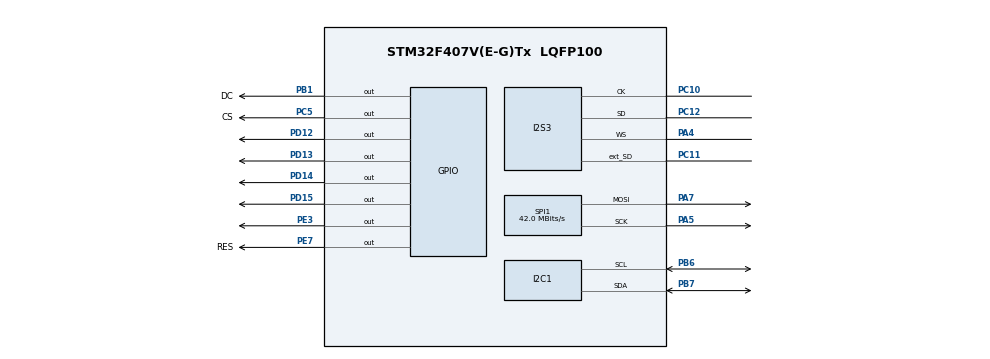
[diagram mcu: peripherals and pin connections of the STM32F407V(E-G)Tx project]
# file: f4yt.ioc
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I2S3.ErrorAudioFreq=0.15 %
I2S3.FullDuplexMode=I2S_FULLDUPLEXMODE_ENABLE
I2S3.Instance=SPI$Index
I2S3.RealAudioFreq=8.012 KHz
I2S3.VirtualMode=I2S_MODE_MASTER
Mcu.Family=STM32F4
Mcu.Name=STM32F407V(E-G)Tx
Mcu.Package=LQFP100
NVIC.PriorityGroup=NVIC_PRIORITYGROUP_0
NVIC.RCC_IRQn=true\:0\:0\:false\:false\:true\:true
PA13.Mode=Serial_Wire
PA13.Signal=SYS_JTMS-SWDIO
PA14.Mode=Serial_Wire
PA14.Signal=SYS_JTCK-SWCLK
PA4.Mode=Full_Duplex_Master
PA4.Signal=I2S3_WS
PA5.Mode=TX_Only_Simplex_Unidirect_Master
PA5.Signal=SPI1_SCK
PA7.Mode=TX_Only_Simplex_Unidirect_Master
PA7.Signal=SPI1_MOSI
PB1.GPIO_Label=DC
PB1.Signal=GPIO_Output
PB6.Mode=I2C
PB6.Signal=I2C1_SCL
PB7.Mode=I2C
PB7.Signal=I2C1_SDA
PC10.Mode=Full_Duplex_Master
PC10.Signal=I2S3_CK
PC11.Mode=Full_Duplex_Master
PC11.Signal=I2S3_ext_SD
PC12.Mode=Full_Duplex_Master
PC12.Signal=I2S3_SD
PC5.GPIO_Label=CS
PC5.Signal=GPIO_Output
PD12.Signal=GPIO_Output
PD13.Signal=GPIO_Output
PD14.Signal=GPIO_Output
PD15.Signal=GPIO_Output
PE3.Signal=GPIO_Output
PE7.GPIO_Label=RES
PE7.Signal=GPIO_Output
PH0-OSC_IN.Mode=HSE-External-Oscillator
PH0-OSC_IN.Signal=RCC_OSC_IN
PH1-OSC_OUT.Mode=HSE-External-Oscillator
PH1-OSC_OUT.Signal=RCC_OSC_OUT
ProjectManager.HeapSize=0x200
ProjectManager.StackSize=0x400
ProjectManager.TargetToolchain=MDK-ARM V5
RCC.48MHZClocksFreq_Value=48000000
RCC.AHBFreq_Value=168000000
RCC.APB1CLKDivider=RCC_HCLK_DIV4
RCC.APB1Freq_Value=42000000
RCC.APB1TimFreq_Value=84000000
RCC.APB2CLKDivider=RCC_HCLK_DIV2
RCC.APB2Freq_Value=84000000
RCC.APB2TimFreq_Value=168000000
RCC.CortexFreq_Value=168000000
RCC.HCLKFreq_Value=168000000
RCC.HSE_VALUE=8000000
RCC.HSI_VALUE=16000000
RCC.LSE_VALUE=32768
RCC.PLLI2SN=50
RCC.PLLM=8
RCC.PLLN=168
RCC.PLLQ=7
RCC.SYSCLKFreq_VALUE=168000000
RCC.SYSCLKSource=RCC_SYSCLKSOURCE_PLLCLK
RCC.VCOOutputFreq_Value=336000000
SPI1.BaudRatePrescaler=SPI_BAUDRATEPRESCALER_2
SPI1.CalculateBaudRate=42.0 MBits/s
SPI1.Direction=SPI_DIRECTION_2LINES
SPI1.Mode=SPI_MODE_MASTER
SPI1.VirtualType=VM_MASTER
board=STM32F4DISCOVERY

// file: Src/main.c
/**
  ******************************************************************************
  * @file           : main.c
  * @brief          : Main program body
  ******************************************************************************
  ** This notice applies to any and all portions of this file
  * that are not between comment pairs USER CODE BEGIN and
  * USER CODE END. Other portions of this file, whether
  * inserted by the user or by software development tools
  * are owned by their respective copyright owners.
  *
  * COPYRIGHT(c) 2018 STMicroelectronics
  *
  * Redistribution and use in source and binary forms, with or without modification,
  * are permitted provided that the following conditions are met:
  *   1. Redistributions of source code must retain the above copyright notice,
  *      this list of conditions and the following disclaimer.
  *   2. Redistributions in binary form must reproduce the above copyright notice,
  *      this list of conditions and the following disclaimer in the documentation
  *      and/or other materials provided with the distribution.
  *   3. Neither the name of STMicroelectronics nor the names of its contributors
  *      may be used to endorse or promote products derived from this software
  *      without specific prior written permission.
  *
  * THIS SOFTWARE IS PROVIDED BY THE COPYRIGHT HOLDERS AND CONTRIBUTORS "AS IS"
  * AND ANY EXPRESS OR IMPLIED WARRANTIES, INCLUDING, BUT NOT LIMITED TO, THE
  * IMPLIED WARRANTIES OF MERCHANTABILITY AND FITNESS FOR A PARTICULAR PURPOSE ARE
  * DISCLAIMED. IN NO EVENT SHALL THE COPYRIGHT HOLDER OR CONTRIBUTORS BE LIABLE
  * FOR ANY DIRECT, INDIRECT, INCIDENTAL, SPECIAL, EXEMPLARY, OR CONSEQUENTIAL
  * DAMAGES (INCLUDING, BUT NOT LIMITED TO, PROCUREMENT OF SUBSTITUTE GOODS OR
  * SERVICES; LOSS OF USE, DATA, OR PROFITS; OR BUSINESS INTERRUPTION) HOWEVER
  * CAUSED AND ON ANY THEORY OF LIABILITY, WHETHER IN CONTRACT, STRICT LIABILITY,
  * OR TORT (INCLUDING NEGLIGENCE OR OTHERWISE) ARISING IN ANY WAY OUT OF THE USE
  * OF THIS SOFTWARE, EVEN IF ADVISED OF THE POSSIBILITY OF SUCH DAMAGE.
  *
  ******************************************************************************
  */
#include "main.h"
#include "stm32f4xx_hal.h"

/* USER CODE BEGIN Includes */
#include "SSD1331.h"
#include "Fonts.h"
#include "stm32f4_discovery.h"

#include "stm32f4_discovery_accelerometer.h"
/* USER CODE END Includes */

I2C_HandleTypeDef hi2c1;

I2S_HandleTypeDef hi2s3;

SPI_HandleTypeDef hspi1;

/* USER CODE BEGIN PV */
/* Private variables ---------------------------------------------------------*/

/* USER CODE END PV */

void SystemClock_Config(void);
static void MX_GPIO_Init(void);
static void MX_SPI1_Init(void);
static void MX_I2C1_Init(void);
static void MX_I2S3_Init(void);

/* USER CODE BEGIN PFP */
/* Private function prototypes -----------------------------------------------*/

/* USER CODE END PFP */

/* USER CODE BEGIN 0 */

bool GameOver;
const int width = 60;
const int height = 40;
int x, y, fruitX, fruitY, score;
int	tailX[100], tailY[100];
int nTail;
enum eDirection {STOP = 0, UP, DOWN, LEFT, RIGHT};
enum eDirection dir;
void Setup() {
	GameOver = false;
	dir = STOP;
	x = width / 2;
	y = height / 2;
	fruitX = rand() % width;
	fruitY = rand() % height;
	score = 0;
}

void Draw() {
	ssd1331_clear_screen(BLACK);   // wyczyszczenie ekranu
	for (int i = 0; i < width; i++) {
		ssd1331_draw_point(i, 0, BLUE);

	}
	//printf(" /n");
	int i;
	for (i=1; i < height; i++) {
		for (int j = 0; j < width; j++) {
			//if (j == 0)
				ssd1331_draw_point(0, i, BLUE);
			if (i == y && j == x){
				ssd1331_draw_point(j, i, GREEN);
				ssd1331_draw_point(j+1, i, GREEN);
				ssd1331_draw_point(j-1, i, GREEN);
				ssd1331_draw_point(j+1, i+1, GREEN);
				ssd1331_draw_point(j+1, i-1, GREEN);
				ssd1331_draw_point(j-1, i+1, GREEN);
				ssd1331_draw_point(j-1, i-1, GREEN);
				ssd1331_draw_point(j, i+1, GREEN);
				ssd1331_draw_point(j, i-1, GREEN);
			}
			else if (i == fruitY && j == fruitX)
				ssd1331_draw_point(j, i, RED);
			else {
				bool print = false;
				for (int k = 0; k < nTail; k++)
				{
					if (tailX[k] == j && tailY[k] == i)
					{
						ssd1331_draw_point(j, i, GREEN);
						print = true;
					}

				}
				if (!print)
					ssd1331_draw_point(j, i, BLACK);
			}
			if (j == width - 1)
				ssd1331_draw_point(j, i, BLUE);
		}
	//	printf(" /n");
		//i++;
	}

	for (int i = 0; i < width ; i++) {
		ssd1331_draw_point(i, 40, BLUE);
	}
	ssd1331_display_string(0, 41, "Score:  ", FONT_1206,YELLOW);
	ssd1331_display_num(35, 41, score, 3, FONT_1206,YELLOW);
}

void Logic() {
	int prevX = tailX[0];
	int prevY = tailY[0];
	int prev2X, prev2Y;
	tailX[0] = x;
	tailY[0] = y;

	for (int i = 1; i < nTail; i++)
	{
		prev2X = tailX[i];
		prev2Y = tailY[i];
		tailX[i] = prevX;
		tailY[i] = prevY;
		prevX = prev2X;
		prevY = prev2Y;
	}

	switch (dir)
	{
	case UP:
		y--;
		break;
	case DOWN:
		y++;
		break;
	case LEFT:
		x--;
		break;
	case RIGHT:
		x++;
		break;
	default:
		break;
	}
	if (x > width || x < 0 || y<0 || y > height)
		GameOver = true;

	for (int i = 0; i < nTail; i++)
	{
		if (tailX[i] == x && tailY[i] == y)
			GameOver = true;
	}
	if ((x == fruitX && y == fruitY )|| (x+1 == fruitX && y == fruitY )|| (x-1 == fruitX && y == fruitY) ||
		(x+1 == fruitX && y+1 == fruitY) ||( x+1 == fruitX && y-1 == fruitY) ||( x-1 == fruitX && y+1 == fruitY )||
		(x-1 == fruitX && y-1 == fruitY) ||( x == fruitX && y+1 == fruitY )||( x == fruitX && y-1 == fruitY))
	{
		score += 10;

		fruitX = rand() % width;
		fruitY = rand() % height;
		nTail++;
	}

}

/* USER CODE END 0 */

int main(void)
{
  /* USER CODE BEGIN 1 */
int16_t xyz[3]={0};
  /* USER CODE END 1 */

  /* MCU Configuration----------------------------------------------------------*/

  /* Reset of all peripherals, Initializes the Flash interface and the Systick. */
  HAL_Init();

  /* Configure the system clock */
  SystemClock_Config();

  /* Initialize all configured peripherals */
  MX_GPIO_Init();
  MX_SPI1_Init();
  MX_I2C1_Init();
  MX_I2S3_Init();
  /* USER CODE BEGIN 2 */

BSP_ACCELERO_Init();
ssd1331_init();

/* USER CODE END 2 */

  /* Infinite loop */
  /* USER CODE BEGIN WHILE */
	Setup();
	while(!GameOver)
	{

			Draw();
		//Input();
		Logic();
		//HAL_Delay(500);

  /* USER CODE END WHILE */

  /* USER CODE BEGIN 3 */
BSP_ACCELERO_GetXYZ(xyz);

		if(xyz[2] <= 920  && xyz[0] <= 300 && xyz[0] >= -300 && xyz[1] <= 100){
 		HAL_GPIO_WritePin(GPIOD, GPIO_PIN_15, GPIO_PIN_SET);
			dir = UP;
 	}else{
 		HAL_GPIO_WritePin(GPIOD, GPIO_PIN_15, GPIO_PIN_RESET);
  }
	if(xyz[0] <= -250 && xyz[1] <= 300){
 		HAL_GPIO_WritePin(GPIOD, GPIO_PIN_12, GPIO_PIN_SET);
		dir = RIGHT;
 	}else{
 		HAL_GPIO_WritePin(GPIOD, GPIO_PIN_12, GPIO_PIN_RESET);
  }
	if(xyz[1] >= 250 ){
 		HAL_GPIO_WritePin(GPIOD, GPIO_PIN_13, GPIO_PIN_SET);
		dir = DOWN;
 	}else{
 		HAL_GPIO_WritePin(GPIOD, GPIO_PIN_13, GPIO_PIN_RESET);
  }
if(xyz[0] >= 300 ){
 		HAL_GPIO_WritePin(GPIOD, GPIO_PIN_14, GPIO_PIN_SET);
	dir = LEFT;
 	}else{
 		HAL_GPIO_WritePin(GPIOD, GPIO_PIN_14, GPIO_PIN_RESET);
  }

}
ssd1331_clear_screen(BLACK);
ssd1331_display_string(20, 21, "GAME OVER!  ", FONT_1206,YELLOW);
ssd1331_display_string(20, 41, "Score:  ", FONT_1206,YELLOW);
ssd1331_display_num(55, 41, score, 3, FONT_1206,YELLOW);
  /* USER CODE END 3 */

}

void SystemClock_Config(void)
{

  RCC_OscInitTypeDef RCC_OscInitStruct;
  RCC_ClkInitTypeDef RCC_ClkInitStruct;
  RCC_PeriphCLKInitTypeDef PeriphClkInitStruct;

    /**Configure the main internal regulator output voltage
    */
  __HAL_RCC_PWR_CLK_ENABLE();

  __HAL_PWR_VOLTAGESCALING_CONFIG(PWR_REGULATOR_VOLTAGE_SCALE1);

    /**Initializes the CPU, AHB and APB busses clocks
    */
  RCC_OscInitStruct.OscillatorType = RCC_OSCILLATORTYPE_HSI;
  RCC_OscInitStruct.HSIState = RCC_HSI_ON;
  RCC_OscInitStruct.HSICalibrationValue =16;
  RCC_OscInitStruct.PLL.PLLState = RCC_PLL_ON;
  RCC_OscInitStruct.PLL.PLLSource = RCC_PLLSOURCE_HSI;
  RCC_OscInitStruct.PLL.PLLM = 8;
  RCC_OscInitStruct.PLL.PLLN =168;
  RCC_OscInitStruct.PLL.PLLP = RCC_PLLP_DIV2;
  RCC_OscInitStruct.PLL.PLLQ = 7;
  if (HAL_RCC_OscConfig(&RCC_OscInitStruct) != HAL_OK)
  {
    _Error_Handler(__FILE__, __LINE__);
  }

    /**Initializes the CPU, AHB and APB busses clocks
    */
  RCC_ClkInitStruct.ClockType = RCC_CLOCKTYPE_HCLK|RCC_CLOCKTYPE_SYSCLK
                              |RCC_CLOCKTYPE_PCLK1|RCC_CLOCKTYPE_PCLK2;
  RCC_ClkInitStruct.SYSCLKSource = RCC_SYSCLKSOURCE_PLLCLK;
  RCC_ClkInitStruct.AHBCLKDivider = RCC_SYSCLK_DIV1;
  RCC_ClkInitStruct.APB1CLKDivider = RCC_HCLK_DIV2;
  RCC_ClkInitStruct.APB2CLKDivider = RCC_HCLK_DIV1;

  if (HAL_RCC_ClockConfig(&RCC_ClkInitStruct, FLASH_LATENCY_3) != HAL_OK)
  {
    _Error_Handler(__FILE__, __LINE__);
  }

  PeriphClkInitStruct.PeriphClockSelection = RCC_PERIPHCLK_I2S;
  PeriphClkInitStruct.PLLI2S.PLLI2SN = 50;
  PeriphClkInitStruct.PLLI2S.PLLI2SR = 2;
  if (HAL_RCCEx_PeriphCLKConfig(&PeriphClkInitStruct) != HAL_OK)
  {
    _Error_Handler(__FILE__, __LINE__);
  }

    /**Configure the Systick interrupt time
    */
  HAL_SYSTICK_Config(HAL_RCC_GetHCLKFreq()/1000);

    /**Configure the Systick
    */
  HAL_SYSTICK_CLKSourceConfig(SYSTICK_CLKSOURCE_HCLK);

  /* SysTick_IRQn interrupt configuration */
  HAL_NVIC_SetPriority(SysTick_IRQn, 0, 0);
}

/* I2C1 init function */
static void MX_I2C1_Init(void)
{

  hi2c1.Instance = I2C1;
  hi2c1.Init.ClockSpeed = 1000000;
  hi2c1.Init.DutyCycle = I2C_DUTYCYCLE_2;
  hi2c1.Init.OwnAddress1 = 0;
  hi2c1.Init.AddressingMode = I2C_ADDRESSINGMODE_7BIT;
  hi2c1.Init.DualAddressMode = I2C_DUALADDRESS_DISABLE;
  hi2c1.Init.OwnAddress2 = 0;
  hi2c1.Init.GeneralCallMode = I2C_GENERALCALL_DISABLE;
  hi2c1.Init.NoStretchMode = I2C_NOSTRETCH_DISABLE;
  if (HAL_I2C_Init(&hi2c1) != HAL_OK)
  {
    _Error_Handler(__FILE__, __LINE__);
  }

}

/* I2S3 init function */
static void MX_I2S3_Init(void)
{

  hi2s3.Instance = SPI3;
  hi2s3.Init.Mode = I2S_MODE_MASTER_TX;
  hi2s3.Init.Standard = I2S_STANDARD_PHILIPS;
  hi2s3.Init.DataFormat = I2S_DATAFORMAT_16B;
  hi2s3.Init.MCLKOutput = I2S_MCLKOUTPUT_DISABLE;
  hi2s3.Init.AudioFreq = I2S_AUDIOFREQ_8K;
  hi2s3.Init.CPOL = I2S_CPOL_LOW;
  hi2s3.Init.ClockSource = I2S_CLOCK_PLL;
  hi2s3.Init.FullDuplexMode = I2S_FULLDUPLEXMODE_ENABLE;
  if (HAL_I2S_Init(&hi2s3) != HAL_OK)
  {
    _Error_Handler(__FILE__, __LINE__);
  }

}

/* SPI1 init function */
static void MX_SPI1_Init(void)
{

  /* SPI1 parameter configuration*/
  hspi1.Instance = SPI1;
  hspi1.Init.Mode = SPI_MODE_MASTER;
  hspi1.Init.Direction = SPI_DIRECTION_2LINES;
  hspi1.Init.DataSize = SPI_DATASIZE_8BIT;
  hspi1.Init.CLKPolarity = SPI_POLARITY_LOW;
  hspi1.Init.CLKPhase = SPI_PHASE_1EDGE;
  hspi1.Init.NSS = SPI_NSS_SOFT;
  hspi1.Init.BaudRatePrescaler = SPI_BAUDRATEPRESCALER_2;
  hspi1.Init.FirstBit = SPI_FIRSTBIT_MSB;
  hspi1.Init.TIMode = SPI_TIMODE_DISABLE;
  hspi1.Init.CRCCalculation = SPI_CRCCALCULATION_DISABLE;
  hspi1.Init.CRCPolynomial = 10;
  if (HAL_SPI_Init(&hspi1) != HAL_OK)
  {
    _Error_Handler(__FILE__, __LINE__);
  }

}

/** Configure pins as
        * Analog
        * Input
        * Output
        * EVENT_OUT
        * EXTI
*/
static void MX_GPIO_Init(void)
{

  GPIO_InitTypeDef GPIO_InitStruct;

  /* GPIO Ports Clock Enable */
  __HAL_RCC_GPIOE_CLK_ENABLE();
  __HAL_RCC_GPIOH_CLK_ENABLE();
  __HAL_RCC_GPIOA_CLK_ENABLE();
  __HAL_RCC_GPIOC_CLK_ENABLE();
  __HAL_RCC_GPIOB_CLK_ENABLE();
  __HAL_RCC_GPIOD_CLK_ENABLE();

  /*Configure GPIO pin Output Level */
  HAL_GPIO_WritePin(GPIOE, GPIO_PIN_3|RES_Pin, GPIO_PIN_RESET);

  /*Configure GPIO pin Output Level */
  HAL_GPIO_WritePin(CS_GPIO_Port, CS_Pin, GPIO_PIN_RESET);

  /*Configure GPIO pin Output Level */
  HAL_GPIO_WritePin(DC_GPIO_Port, DC_Pin, GPIO_PIN_RESET);

  /*Configure GPIO pin Output Level */
  HAL_GPIO_WritePin(GPIOD, GPIO_PIN_12|GPIO_PIN_13|GPIO_PIN_14|GPIO_PIN_15, GPIO_PIN_RESET);

  /*Configure GPIO pins : PE3 RES_Pin */
  GPIO_InitStruct.Pin = GPIO_PIN_3|RES_Pin;
  GPIO_InitStruct.Mode = GPIO_MODE_OUTPUT_PP;
  GPIO_InitStruct.Pull = GPIO_NOPULL;
  GPIO_InitStruct.Speed = GPIO_SPEED_FREQ_LOW;
  HAL_GPIO_Init(GPIOE, &GPIO_InitStruct);

  /*Configure GPIO pin : CS_Pin */
  GPIO_InitStruct.Pin = CS_Pin;
  GPIO_InitStruct.Mode = GPIO_MODE_OUTPUT_PP;
  GPIO_InitStruct.Pull = GPIO_NOPULL;
  GPIO_InitStruct.Speed = GPIO_SPEED_FREQ_LOW;
  HAL_GPIO_Init(CS_GPIO_Port, &GPIO_InitStruct);

  /*Configure GPIO pin : DC_Pin */
  GPIO_InitStruct.Pin = DC_Pin;
  GPIO_InitStruct.Mode = GPIO_MODE_OUTPUT_PP;
  GPIO_InitStruct.Pull = GPIO_NOPULL;
  GPIO_InitStruct.Speed = GPIO_SPEED_FREQ_LOW;
  HAL_GPIO_Init(DC_GPIO_Port, &GPIO_InitStruct);

  /*Configure GPIO pins : PD12 PD13 PD14 PD15 */
  GPIO_InitStruct.Pin = GPIO_PIN_12|GPIO_PIN_13|GPIO_PIN_14|GPIO_PIN_15;
  GPIO_InitStruct.Mode = GPIO_MODE_OUTPUT_PP;
  GPIO_InitStruct.Pull = GPIO_NOPULL;
  GPIO_InitStruct.Speed = GPIO_SPEED_FREQ_LOW;
  HAL_GPIO_Init(GPIOD, &GPIO_InitStruct);

}

void _Error_Handler(char *file, int line)
{
  while(1)
  {
  }
}

/************************ (C) COPYRIGHT STMicroelectronics *****END OF FILE****/
